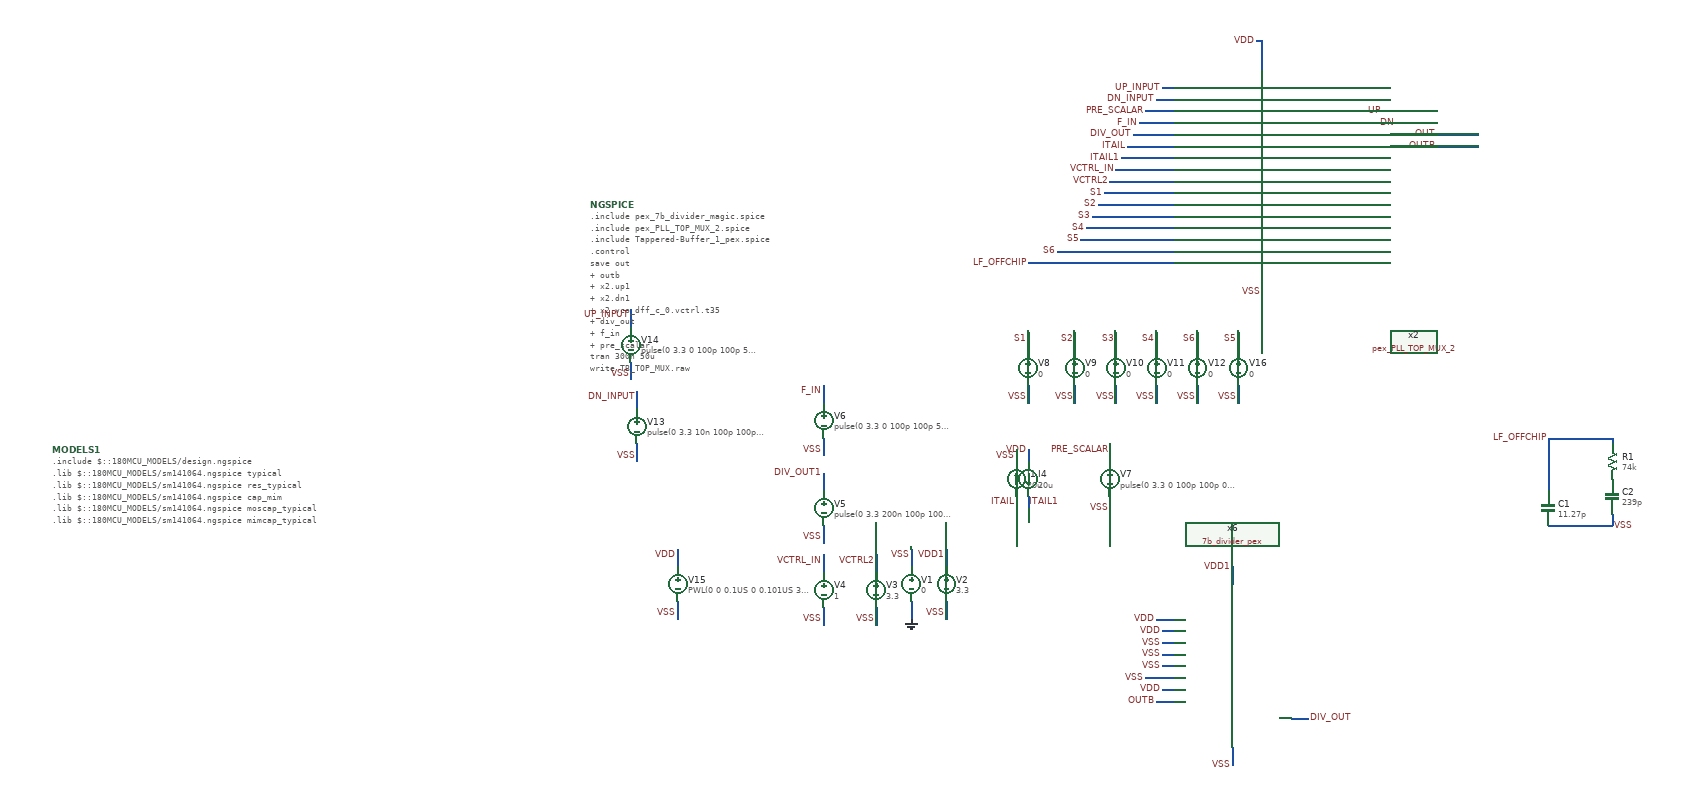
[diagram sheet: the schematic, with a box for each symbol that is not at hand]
v {xschem version=3.4.3 file_version=1.2
}
G {}
K {}
V {}
S {}
E {}
B 2 940 -940 1730 -690 {flags=graph
y1=-0.075996
y2=0.177695
ypos1=0
ypos2=2
divy=5
subdivy=1
unity=1
x1=-8.76e-07
x2=3.5272e-06
divx=5
subdivx=1
xlabmag=1.0
ylabmag=1.0
node=x2.vco_dff_c_0.vctrl.t35
color=4
dataset=-1
unitx=1
logx=0
logy=0
hilight_wave=0}
B 2 940 -620 1730 -370 {flags=graph
y1=-0.075
y2=3.4
ypos1=0
ypos2=2
divy=5
subdivy=1
unity=1
x1=-8.76e-07
x2=3.5272e-06
divx=5
subdivx=1
xlabmag=1.0
ylabmag=1.0
node=x2.up1
color=4
dataset=-1
unitx=1
logx=0
logy=0
}
B 2 960 -300 1750 -50 {flags=graph
y1=-0.096
y2=3.4
ypos1=0
ypos2=2
divy=5
subdivy=1
unity=1
x1=-8.76e-07
x2=3.5272e-06
divx=5
subdivx=1
xlabmag=1.0
ylabmag=1.0


dataset=-1
unitx=1
logx=0
logy=0
color=4
node=x2.dn1}
B 2 950 20 1740 270 {flags=graph
y1=-0.059
y2=3.4
ypos1=0
ypos2=2
divy=5
subdivy=1
unity=1
x1=-8.76e-07
x2=3.5272e-06
divx=5
subdivx=1
xlabmag=1.0
ylabmag=1.0


dataset=-1
unitx=1
logx=0
logy=0





color=4
node=out}
B 2 950 300 1740 550 {flags=graph
y1=-0.046
y2=3.4
ypos1=0
ypos2=2
divy=5
subdivy=1
unity=1
x1=-8.76e-07
x2=3.5272e-06
divx=5
subdivx=1
xlabmag=1.0
ylabmag=1.0


dataset=-1
unitx=1
logx=0
logy=0





color=4
node=div_out}
B 2 1830 -940 2620 -690 {flags=graph
y1=0
y2=3.3
ypos1=0
ypos2=2
divy=5
subdivy=1
unity=1
x1=-8.76e-07
x2=3.5272e-06
divx=5
subdivx=1
xlabmag=1.0
ylabmag=1.0
node=f_in
color=4
dataset=-1
unitx=1
logx=0
logy=0
hilight_wave=0}
B 2 1830 -620 2620 -370 {flags=graph
y1=-0.026
y2=3.4
ypos1=0
ypos2=2
divy=5
subdivy=1
unity=1
x1=-8.76e-07
x2=3.5272e-06
divx=5
subdivx=1
xlabmag=1.0
ylabmag=1.0
node=div_out
color=4
dataset=-1
unitx=1
logx=0
logy=0
hilight_wave=0}
B 2 1820 -310 2610 -60 {flags=graph
y1=-0.096
y2=3.4
ypos1=0
ypos2=2
divy=5
subdivy=1
unity=1
x1=-8.76e-07
x2=3.5272e-06
divx=5
subdivx=1
xlabmag=1.0
ylabmag=1.0


dataset=-1
unitx=1
logx=0
logy=0
color=4
node=x2.dn1}
B 2 1820 10 2610 260 {flags=graph
y1=-0.096
y2=3.4
ypos1=0
ypos2=2
divy=5
subdivy=1
unity=1
x1=-8.76e-07
x2=3.5272e-06
divx=5
subdivx=1
xlabmag=1.0
ylabmag=1.0


dataset=-1
unitx=1
logx=0
logy=0
color=4
node=x2.up1}
N -700 -80 -700 -50 {
lab=GND}
N -700 -170 -700 -140 {
lab=VSS}
N -640 -170 -640 -140 {
lab=VDD1}
N -640 -80 -640 -50 {
lab=VSS}
N -760 -160 -760 -130 {
lab=VCTRL2}
N -760 -70 -760 -40 {
lab=VSS}
N -850 -160 -850 -130 {
lab=VCTRL_IN}
N -850 -70 -850 -40 {
lab=VSS}
N -850 -300 -850 -270 {
lab=DIV_OUT1}
N -850 -210 -850 -180 {
lab=VSS}
N -850 -450 -850 -420 {
lab=F_IN}
N -850 -360 -850 -330 {
lab=VSS}
N -500 -340 -500 -320 {
lab=VDD}
N -520 -340 -520 -320 {
lab=VSS}
N -500 -260 -500 -240 {
lab=ITAIL1}
N -520 -260 -520 -250 {
lab=ITAIL}
N -500 -540 -500 -510 {
lab=S1}
N -500 -450 -500 -420 {
lab=VSS}
N -420 -540 -420 -510 {
lab=S2}
N -420 -450 -420 -420 {
lab=VSS}
N -350 -540 -350 -510 {
lab=S3}
N -350 -450 -350 -420 {
lab=VSS}
N -280 -540 -280 -510 {
lab=S4}
N -280 -450 -280 -420 {
lab=VSS}
N -210 -540 -210 -510 {
lab=S6}
N -210 -450 -210 -420 {
lab=VSS}
N -360 -350 -360 -320 {
lab=PRE_SCALAR}
N -360 -260 -360 -230 {
lab=VSS}
N -1170 -440 -1170 -410 {
lab=DN_INPUT}
N -1170 -350 -1170 -320 {
lab=VSS}
N -1180 -580 -1180 -550 {
lab=UP_INPUT}
N -1180 -490 -1180 -460 {
lab=VSS}
N -100 -1040 -100 -990 {
lab=VDD}
N 50 -920 80 -920 {
lab=UP}
N 50 -900 100 -900 {
lab=DN}
N -270 -960 -250 -960 {
lab=UP_INPUT}
N -280 -940 -250 -940 {
lab=DN_INPUT}
N -300 -920 -250 -920 {
lab=PRE_SCALAR}
N -310 -900 -250 -900 {
lab=F_IN}
N -320 -880 -250 -880 {
lab=DIV_OUT}
N -330 -860 -250 -860 {
lab=ITAIL}
N -340 -840 -250 -840 {
lab=ITAIL1}
N -350 -820 -250 -820 {
lab=VCTRL_IN}
N -360 -800 -250 -800 {
lab=VCTRL2}
N -370 -780 -250 -780 {
lab=S1}
N -380 -760 -250 -760 {
lab=S2}
N -390 -740 -250 -740 {
lab=S3}
N -400 -720 -250 -720 {
lab=S4}
N -410 -700 -250 -700 {
lab=S5}
N -100 -630 -100 -610 {
lab=VSS}
N 50 -880 270 -880 {
lab=OUT}
N 50 -860 270 -860 {
lab=OUTB}
N -1100 -170 -1100 -140 {
lab=VDD}
N -1100 -80 -1100 -50 {
lab=VSS}
N -110 -1040 -100 -1040 {
lab=VDD}
N -450 -680 -250 -680 {
lab=S6}
N -500 -660 -250 -660 {
lab=LF_OFFCHIP}
N 390 -210 500 -210 {
lab=VSS}
N 500 -230 500 -210 {
lab=VSS}
N 390 -360 390 -270 {
lab=LF_OFFCHIP}
N 390 -360 500 -360 {
lab=LF_OFFCHIP}
N 500 -360 500 -350 {
lab=LF_OFFCHIP}
N -140 -540 -140 -510 {
lab=S5}
N -140 -450 -140 -420 {
lab=VSS}
N -150 -140 -150 -110 {
lab=VDD1}
N -280 90 -250 90 {
lab=OUTB}
N -150 170 -150 200 {
lab=VSS}
N -50 120 -20 120 {
lab=DIV_OUT}
N -280 -50 -250 -50 {
lab=VDD}
N -270 -30 -250 -30 {
lab=VDD}
N -270 -10 -250 -10 {
lab=VSS}
N -270 10 -250 10 {
lab=VSS}
N -270 30 -250 30 {
lab=VSS}
N -270 70 -250 70 {
lab=VDD}
N -270 50 -250 50 {
lab=VSS}
N -300 50 -270 50 {
lab=VSS}
C {devices/code_shown.sym} -1250 -760 0 1 {name=NGSPICE only_toplevel=true
value="
.include "pex_7b_divider_magic.spice"
.include "pex_PLL_TOP_MUX_2.spice"
.include "Tappered-Buffer_1_pex.spice"
.control
save out
+ outb
+ x2.up1
+ x2.dn1
+ x2.vco_dff_c_0.vctrl.t35
+ div_out
+ f_in
+ pre_scalar

tran 300n 50u

write TB_TOP_MUX.raw
.endc
"}
C {devices/code_shown.sym} -2170 -340 0 0 {name=MODELS1 only_toplevel=true
format="tcleval( @value )"
value="
.include $::180MCU_MODELS/design.ngspice
.lib $::180MCU_MODELS/sm141064.ngspice typical
.lib $::180MCU_MODELS/sm141064.ngspice res_typical
.lib $::180MCU_MODELS/sm141064.ngspice cap_mim
.lib $::180MCU_MODELS/sm141064.ngspice moscap_typical
.lib $::180MCU_MODELS/sm141064.ngspice mimcap_typical
"}
C {devices/vsource.sym} -700 -110 0 0 {name=V1 value=0}
C {devices/vsource.sym} -640 -110 0 0 {name=V2 value=3.3}
C {devices/gnd.sym} -700 -50 0 0 {name=l1 lab=GND}
C {devices/lab_wire.sym} -700 -160 0 0 {name=p1 sig_type=std_logic lab=VSS}
C {devices/lab_wire.sym} -640 -160 0 0 {name=p4 sig_type=std_logic lab=VDD1}
C {devices/vsource.sym} -760 -100 0 0 {name=V3 value=3.3}
C {devices/lab_wire.sym} -760 -150 0 0 {name=p6 sig_type=std_logic lab=VCTRL2}
C {devices/lab_wire.sym} -640 -60 0 0 {name=p8 sig_type=std_logic lab=VSS}
C {devices/lab_wire.sym} -760 -50 0 0 {name=p9 sig_type=std_logic lab=VSS}
C {devices/vsource.sym} -850 -100 0 0 {name=V4 value=1}
C {devices/lab_wire.sym} -850 -150 0 0 {name=p3 sig_type=std_logic lab=VCTRL_IN}
C {devices/lab_wire.sym} -850 -50 0 0 {name=p5 sig_type=std_logic lab=VSS}
C {devices/vsource.sym} -850 -240 0 0 {name=V5 value="pulse(0 3.3 200n 100p 100p 500n 1000n)"}
C {devices/lab_wire.sym} -850 -190 0 0 {name=p38 sig_type=std_logic lab=VSS}
C {devices/vsource.sym} -850 -390 0 0 {name=V6 value="pulse(0 3.3 0 100p 100p 500n 1000n)"}
C {devices/lab_wire.sym} -850 -340 0 0 {name=p40 sig_type=std_logic lab=VSS}
C {devices/lab_wire.sym} -850 -440 0 0 {name=p41 sig_type=std_logic lab=F_IN}
C {devices/lab_wire.sym} -850 -300 0 0 {name=p23 sig_type=std_logic lab=DIV_OUT1}
C {devices/isource.sym} -520 -290 2 0 {name=I1 value=20u}
C {devices/isource.sym} -500 -290 0 0 {name=I4 value=20u}
C {devices/lab_wire.sym} -500 -340 0 0 {name=p29 sig_type=std_logic lab=VDD}
C {devices/lab_wire.sym} -520 -330 0 0 {name=p30 sig_type=std_logic lab=VSS}
C {devices/lab_wire.sym} -520 -250 0 0 {name=p35 sig_type=std_logic lab=ITAIL}
C {devices/lab_wire.sym} -500 -250 2 0 {name=p36 sig_type=std_logic lab=ITAIL1}
C {devices/vsource.sym} -500 -480 0 0 {name=V8 value=0}
C {devices/lab_wire.sym} -500 -530 0 0 {name=p31 sig_type=std_logic lab=S1}
C {devices/lab_wire.sym} -500 -430 0 0 {name=p32 sig_type=std_logic lab=VSS}
C {devices/vsource.sym} -420 -480 0 0 {name=V9 value=0}
C {devices/lab_wire.sym} -420 -530 0 0 {name=p33 sig_type=std_logic lab=S2}
C {devices/lab_wire.sym} -420 -430 0 0 {name=p34 sig_type=std_logic lab=VSS}
C {devices/vsource.sym} -350 -480 0 0 {name=V10 value=0}
C {devices/lab_wire.sym} -350 -530 0 0 {name=p37 sig_type=std_logic lab=S3}
C {devices/lab_wire.sym} -350 -430 0 0 {name=p39 sig_type=std_logic lab=VSS}
C {devices/vsource.sym} -280 -480 0 0 {name=V11 value=0}
C {devices/lab_wire.sym} -280 -530 0 0 {name=p42 sig_type=std_logic lab=S4}
C {devices/lab_wire.sym} -280 -430 0 0 {name=p43 sig_type=std_logic lab=VSS}
C {devices/vsource.sym} -210 -480 0 0 {name=V12 value=0}
C {devices/lab_wire.sym} -210 -530 0 0 {name=p44 sig_type=std_logic lab=S6}
C {devices/lab_wire.sym} -210 -430 0 0 {name=p45 sig_type=std_logic lab=VSS}
C {devices/vsource.sym} -360 -290 0 0 {name=V7 value="pulse(0 3.3 0 100p 100p 0.5u 1u)"}
C {devices/lab_wire.sym} -360 -240 0 0 {name=p46 sig_type=std_logic lab=VSS}
C {devices/lab_wire.sym} -360 -340 0 0 {name=p47 sig_type=std_logic lab=PRE_SCALAR}
C {devices/vsource.sym} -1170 -380 0 0 {name=V13 value="pulse(0 3.3 10n 100p 100p 500n 1000n)"}
C {devices/lab_wire.sym} -1170 -330 0 0 {name=p48 sig_type=std_logic lab=VSS}
C {devices/lab_wire.sym} -1170 -430 0 0 {name=p49 sig_type=std_logic lab=DN_INPUT}
C {devices/vsource.sym} -1180 -520 0 0 {name=V14 value="pulse(0 3.3 0 100p 100p 500n 1000n)"}
C {devices/lab_wire.sym} -1180 -470 0 0 {name=p50 sig_type=std_logic lab=VSS}
C {devices/lab_wire.sym} -1180 -570 0 0 {name=p51 sig_type=std_logic lab=UP_INPUT}
C {devices/lab_wire.sym} -270 -960 0 0 {name=p52 sig_type=std_logic lab=UP_INPUT}
C {devices/lab_wire.sym} -280 -940 0 0 {name=p53 sig_type=std_logic lab=DN_INPUT}
C {devices/lab_wire.sym} -300 -920 0 0 {name=p54 sig_type=std_logic lab=PRE_SCALAR
}
C {devices/lab_wire.sym} -310 -900 0 0 {name=p55 sig_type=std_logic lab=F_IN}
C {devices/lab_wire.sym} -320 -880 0 0 {name=p56 sig_type=std_logic lab=DIV_OUT}
C {devices/lab_wire.sym} -330 -860 0 0 {name=p57 sig_type=std_logic lab=ITAIL
}
C {devices/lab_wire.sym} -340 -840 0 0 {name=p58 sig_type=std_logic lab=ITAIL1}
C {devices/lab_wire.sym} -350 -820 0 0 {name=p59 sig_type=std_logic lab=VCTRL_IN}
C {devices/lab_wire.sym} -360 -800 0 0 {name=p60 sig_type=std_logic lab=VCTRL2}
C {devices/lab_wire.sym} -370 -780 0 0 {name=p61 sig_type=std_logic lab=S1}
C {devices/lab_wire.sym} -380 -760 0 0 {name=p62 sig_type=std_logic lab=S2}
C {devices/lab_wire.sym} -390 -740 0 0 {name=p63 sig_type=std_logic lab=S3}
C {devices/lab_wire.sym} -400 -720 0 0 {name=p64 sig_type=std_logic lab=S4}
C {devices/lab_wire.sym} -410 -700 0 0 {name=p65 sig_type=std_logic lab=S5}
C {devices/lab_wire.sym} -100 -610 0 0 {name=p66 sig_type=std_logic lab=VSS}
C {devices/lab_wire.sym} -110 -1040 0 0 {name=p67 sig_type=std_logic lab=VDD}
C {devices/lab_wire.sym} 80 -920 2 0 {name=p68 sig_type=std_logic lab=UP}
C {devices/lab_wire.sym} 100 -900 2 0 {name=p69 sig_type=std_logic lab=DN}
C {devices/lab_wire.sym} 200 -880 1 0 {name=p76 sig_type=std_logic lab=OUT}
C {devices/lab_wire.sym} 200 -860 3 0 {name=p77 sig_type=std_logic lab=OUTB}
C {devices/vsource.sym} -1100 -110 0 0 {name=V15 value="PWL(0 0 0.1US 0 0.101US 3.3)"}
C {devices/lab_wire.sym} -1100 -160 0 0 {name=p78 sig_type=std_logic lab=VDD}
C {devices/lab_wire.sym} -1100 -60 0 0 {name=p79 sig_type=std_logic lab=VSS}
C {pex_PLL_TOP_MUX_2.sym} -100 -810 0 0 {name=x2}
C {devices/lab_wire.sym} -450 -680 0 0 {name=p82 sig_type=std_logic lab=S6}
C {devices/lab_wire.sym} -500 -660 0 0 {name=p83 sig_type=std_logic lab=LF_OFFCHIP}
C {devices/capa.sym} 390 -240 0 0 {name=C1
m=1
value=11.27p
footprint=1206
device="ceramic capacitor"}
C {devices/res.sym} 500 -320 0 0 {name=R1
value=74k
footprint=1206
device=resistor
m=1}
C {devices/capa.sym} 500 -260 0 0 {name=C2
m=1
value=239p
footprint=1206
device="ceramic capacitor"}
C {devices/lab_wire.sym} 500 -210 2 0 {name=p84 sig_type=std_logic lab=VSS}
C {devices/lab_wire.sym} 390 -360 0 0 {name=p85 sig_type=std_logic lab=LF_OFFCHIP}
C {devices/vsource.sym} -140 -480 0 0 {name=V16 value=0}
C {devices/lab_wire.sym} -140 -530 0 0 {name=p86 sig_type=std_logic lab=S5}
C {devices/lab_wire.sym} -140 -430 0 0 {name=p87 sig_type=std_logic lab=VSS}
C {devices/lab_wire.sym} -150 -140 0 0 {name=p88 sig_type=std_logic lab=VDD1}
C {devices/lab_wire.sym} -150 200 0 0 {name=p89 sig_type=std_logic lab=VSS}
C {devices/lab_wire.sym} -280 90 2 1 {name=p90 sig_type=std_logic lab=OUTB}
C {devices/lab_wire.sym} -280 -50 0 0 {name=p92 sig_type=std_logic lab=VDD}
C {devices/lab_wire.sym} -270 -10 0 0 {name=p93 sig_type=std_logic lab=VSS}
C {devices/lab_wire.sym} -270 30 0 0 {name=p94 sig_type=std_logic lab=VSS}
C {7b_divider_pex.sym} -100 30 0 0 {name=x6}
C {devices/lab_wire.sym} -270 -30 0 0 {name=p95 sig_type=std_logic lab=VDD}
C {devices/lab_wire.sym} -270 10 0 0 {name=p96 sig_type=std_logic lab=VSS}
C {devices/lab_wire.sym} -300 50 0 0 {name=p97 sig_type=std_logic lab=VSS}
C {devices/lab_wire.sym} -270 70 0 0 {name=p98 sig_type=std_logic lab=VDD}
C {devices/lab_wire.sym} -20 120 2 0 {name=p99 sig_type=std_logic lab=DIV_OUT}
